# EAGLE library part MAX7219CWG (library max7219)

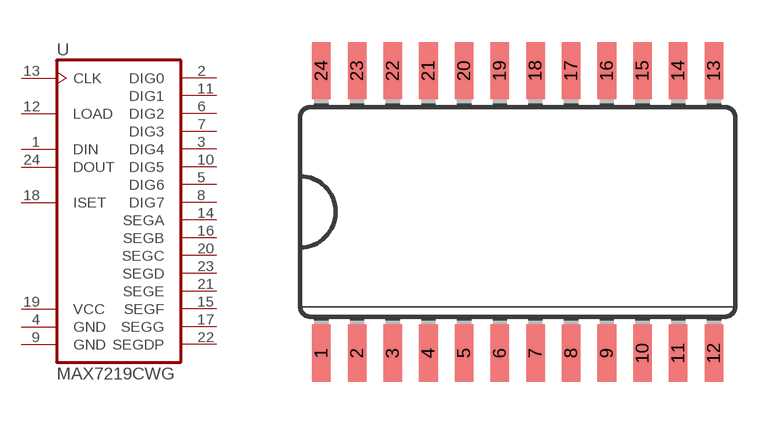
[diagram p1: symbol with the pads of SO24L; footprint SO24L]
Designator prefix -

## MAX7219CWG  [SO24L]
1  DIN  in
2  DIG0  out
3  DIG4  out
4  GND  pwr
5  DIG6  out
6  DIG2  out
7  DIG3  out
8  DIG7  out
9  GND  pwr
10  DIG5  out
11  DIG1  out
12  LOAD  in
13  CLK  in
14  SEGA  out
15  SEGF  out
16  SEGB  out
17  SEGG  out
18  ISET  in
19  VCC  pwr
20  SEGC  out
21  SEGE  out
22  SEGDP  out
23  SEGD  out
24  DOUT  out

## Footprint SO24L (pad centres in mm)
Small Outline Package
smd 0.66 x 2.032: 1 -6.985,-5.029; 2 -5.715,-5.029; 3 -4.445,-5.029; 4 -3.175,-5.029; 5 -1.905,-5.029; 6 -0.635,-5.029; 7 0.635,-5.029; 8 1.905,-5.029; 9 3.175,-5.029; 10 4.445,-5.029; 11 5.715,-5.029; 12 6.985,-5.029; 13 6.985,5.029; 14 5.715,5.029; 15 4.445,5.029; 16 3.175,5.029; 17 1.905,5.029; 18 0.635,5.029; 19 -0.635,5.029; 20 -1.905,5.029; 21 -3.175,5.029; 22 -4.445,5.029; 23 -5.715,5.029; 24 -6.985,5.029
